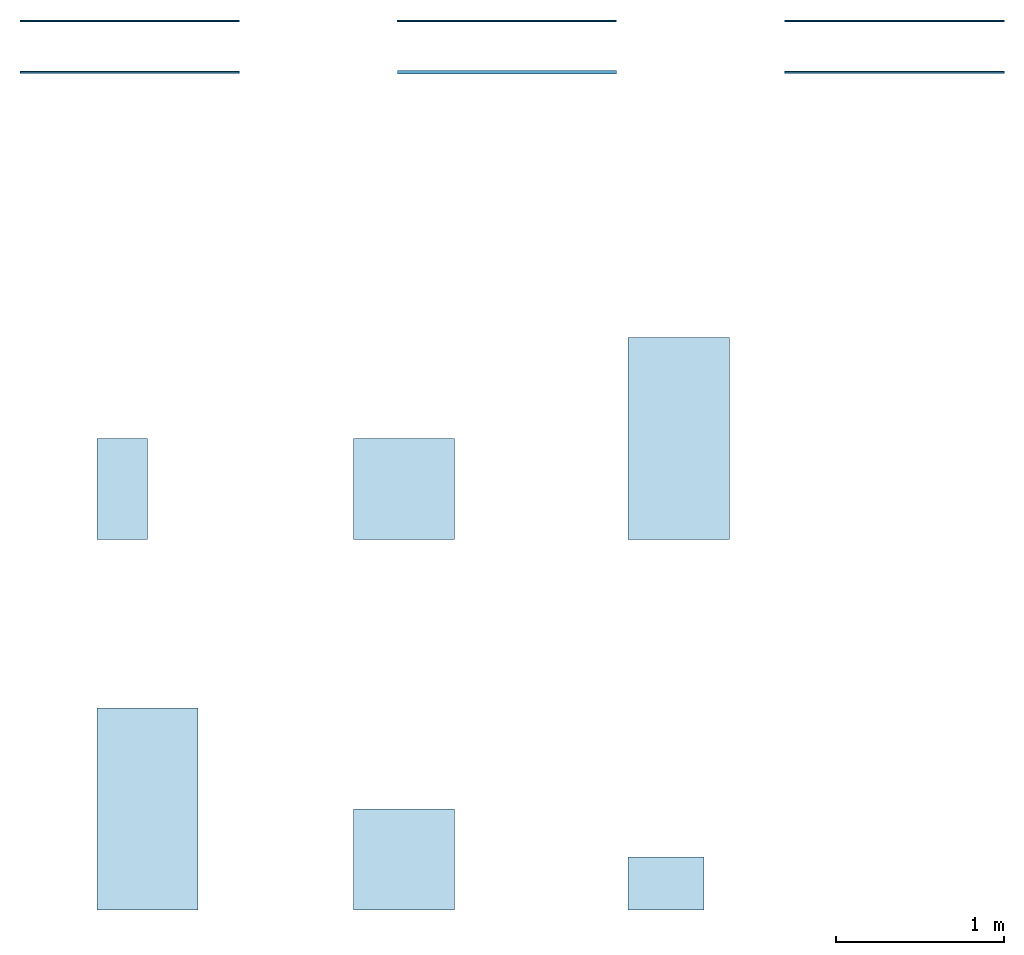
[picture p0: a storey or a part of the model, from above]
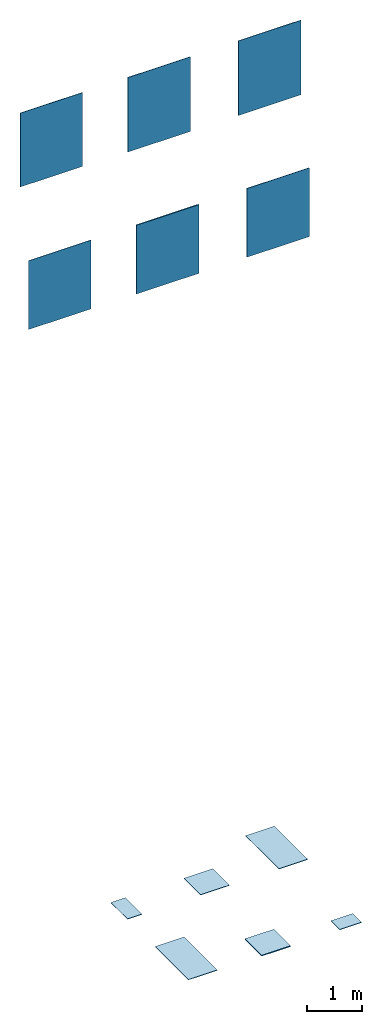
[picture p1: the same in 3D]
Properties of the parts of a building model (IFC2X3), part 2 of 2

# IfcWallStandardCase: Basic Wall:Wall_Tiles_Refin-Blended-Dark-60x60 OA84, Basic Wall:Wall_Tiles_Refin-Blended-Dark-60x60 OA84:333696
Type - Pset_CoveringCommon - Reference: N/A; Status: N/A; AcousticRating: N/A; FlammabilityRating: INERT; FragilityRating: INERT; Combustible: FALSE; SurfaceSpreadOfFlame: INERT; Finish: MATT; IsExternal: N/A; ThermalTransmittance: N/A; FireRating: INERT
Type - Pset_CoveringFlooring - HasNonSkidSurface: TRUE; HasAntiStaticSurface: FALSE
Type - Pset_Condition - AssessmentDate: N/A; AssessmentCondition: N/A; AssessmentDescription: N/A
Type - Pset_ServiceLife - ServiceLifeDuration: N/A; MeanTimeBetweenFailure: N/A
Type - COBie - AccessibilityPerformance: N/A; AssetIdentifier: N/A; AssetType: FIXED; BarCode: N/A; Category: Pr_35_93_96_19:Ceramic tiles; CodePerformance: BS 5385; Color: DARK; Constituents: N/A; Description: PORCELAIN STONEWARE TILE; DurationUnit: YEAR; ExpectedLife: N/A; Features: N/A; Grade: N/A; InstallationDate: 31/12/1900 23:59:59; Manufacturer: info@refin.it; Material: PORCELAIN STONEWARE; ModelNumber: OA84; ModelReference: OA84; Name: Blended_Dark_60X60 R; NominalHeight: 9 mm; NominalLength: 600 mm; NominalWidth: 600 mm; ReplacementCost: N/A; SerialNumber: N/A; Shape: SQUARE; Size: 60X60; SustainabilityPerformance: N/A; TagNumber: N/A; WarrantyDescription: N/A; WarrantyDurationLabor: N/A; WarrantyDurationParts: N/A; WarrantyDurationUnit: YEAR; WarrantyGuarantorLabor: N/A; WarrantyGuarantorParts: N/A; WarrantyStartDate: 31/12/1900 23:59:59
Type - DoPAndProductCertification - HarmonizedTechnicalSpecification: EN 14411:2015; DeclarationPerformanceNumber: CPR_01; UniqueIdentificationCodeOfTheProductType: Dry-pressed ceramic tiles,with water absorption Eb<0,5%; SystemOfAssessmentAndVerificationOfCostancyOfPperformance (AVCP): SYSTEM 4; NameAndIdentificationNumberOfNotifiedLaboratory: N/A; CertificateNumber: N/A; ReactionToFire: A1FL/A1; ReleaseOfDangerousSubstanceCadmium: NPD mg/dm2; ReleaseOfDangerousSubstanceLead: NPD mg/dm2; BreakingStrength: > 1300 N; BondStrengthAdhesion: NPD N/mm2; ThermalShockResistance: PASS; Tactility: NPD; DurabilityForInternalUse: PASS; DurabilityExternalUseFreezeThawResistance: PASS; VoluntaryOrNotSubjectToCEMarking: Y/N; IntendedUse: INTERNAL/EXTERNAL; TensileStrengthOrModulusOfRupture: > 35 N/mm2; SlipperinessDIN51130_RampWithOil: R10; SlipperinessDIN51097_RampBarefoot: N/A; SlipperinessDIN51131_Tribometer: N/A; SlipperinessBS7976-2_PendulumTester: ≥ 36 Wet; SlipperinessENV12633_PendulumTester: RD = N/A; SlipperinessXPCENTS16165_RampTest: N/A; SlipperinessBCRA_Tribometer: Asciutto > 0,40 / Bagnato > 0,40; SlipperinessBOT3000_Tribometer: > 0,42 Wet; UPECMarkCertification: N/A; UNIMarkCertification: N/A
Type - OtherThecnicalFeatures - DimensionsLengthAndWidth: 0.3; DimensionsThickness: 5; DimensionsStraightness: 0.3; DimensionsRectangularity: 0.3; DimensionsSurfaceFlatness: 0.4; SurfaceQuality: 5; WaterAbsorption: Ev<0.5%; ApparentDensity: N/A g/cm3; ModulusOfRupture: > 35 N/mm2; ImpactResistance: > 0.55; DeepAbrasionResistance: < 175 mm3; SurfaceAbrasionResistance: N/A (classe); LinearThermalExpansion: < 7 10-6/°C; MoistureExpansion: < 0.01; CrazingResistance: N/A; FrostResistance: RESISTENTE; ChemicalResistance: A,LA,HA (classe); StainsResistance: 5 (classe); ThermalConductivity: 1.3 W/m.K; ElectricalConductivity: N/A MW; CompressionResistance: 250 Mpa; HardnessMohsScale: N/A (classe); Light ReflectanceValueLRV: 16 %; LightAndColourFastness: N/A
Type - Ambiental Sustainability - EPDType: PRODUCT-SPECIFIC TYPE III EPD; EPDDocument: https://www.refin.it/download/certifications/REFIN_EPD_it.pdf; EnvironmentalProductDeclarationEPD: Y; ISO9001Certification: https://www.refin.it/download/certifications/iso9001.pdf; Ecolabel UE: Y/N; EcolabelCertification: https://www.refin.it/download/certifications/PEF_CeramicheRefin_IT.pdf; EMASCertification/Document: N/A; HealthProductDeclarationHPDCertification/self declaration: N/A; FicheDeDéclarationEnvironnementaleEtSanitaireFDESCertification: https://www.refin.it/download/certifications/refin_fdes.pdf; RecycledContentPreconsumerCertification: https://www.refin.it/download/certifications/leed.pdf; SolarReflectance_InitialValue: 25; SolarReflectance_After3YearValue: N/A; SolarReflectanceCertification: N/A; SolarReflectanceIndexSRICertification: N/A; ZeroVOCMineralBasedProduct: Y; VOCIndoorAirQualityCertification: N/A; RawMaterialSourceAndExtractionDocument: N/A; RecyclableProductPackaging: Y; REACHCompliant: Y; AsbestosFreeMaterial: Y; FormaldehydeFreeMaterial: Y; CAMCompliantDeclaration: N/A; ISO45001Certification: N/A; ISO50001Certification: N/A
Type - Pset_EnvironmentalImpactIndicator - Reference: N/A; FunctionalUnitReference: N/A; Unit: m2; LifeCyclePhase: A1,A2,A3,A4,A5,B1,B2,B3,B4,B5,B6,B7,C1,C2,C3,C4,D; ExpectedServiceLife: 60 YEARS; TotalPrimaryEnergyConsumptionPerUnit: 234; WaterConsumptionPerUnit: 0.0522; HazardousWastePerUnit: 0.00301; NonHazardousWastePerUnit: 10.4; ClimateChangePerUnit: 12.8; AtmosphericAcidificationPerUnit: 0.0485; RenewableEnergyConsumptionPerUnit: 44.5; NonRenewableEnergyConsumptionPerUnit: 189; ResourceDepletionPerUnit: 0.0000365; InertWastePerUnit: N/A; RadioactiveWastePerUnit: 0.00254; StratosphericOzoneLayerDestructionPerUnit: 0.0000000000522; PhotochemicalOzoneFormationPerUnit: 0.00302; EutrophicationPerUnit: 0.00445
Type - Pset_EnvironmentalImpactValues - TotalPrimaryEnergyConsumption: N/A; WaterConsumption: N/A; HazardousWaste: N/A; NonHazardousWaste: N/A; ClimateChange: N/A; AtmosphericAcidification: N/A; RenewableEnergyConsumption: N/A; NonRenewableEnergyConsumption: N/A; ResourceDepletion: N/A; InertWaste: N/A; RadioactiveWaste: N/A; StratosphericOzoneLayerDestruction: N/A; PhotochemicalOzoneFormation: N/A; Eutrophication: N/A; LeadInTime: N/A; Duration: N/A; LeadOutTime: N/A
Pset_ProductRequirements - Category: Walls
Pset_WallCommon - LoadBearing: no; ExtendToStructure: no
COBie - Category: Walls

# IfcWallStandardCase: Basic Wall:Wall_Tiles_Refin-Blended-Dark-GRIP-60x120 OB65, Basic Wall:Wall_Tiles_Refin-Blended-Dark-GRIP-60x120 OB65:335038
In: Level 0
Type - PredefinedType: STANDARD; Material: <Unnamed> 1 mm, Blended-Dark-GRIP-60x120 OB65 9 mm
Type - Pset_ConcreteElementGeneral - FireRating: INERT
Type - Pset_ElementShading - Roughness: 914.4 mm; Color: DARK
Type - Pset_FireRatingProperties - SurfaceSpreadOfFlame: INERT
Type - Pset_ManufacturerOccurrence - BarCode: N/A; SerialNumber: N/A
Type - Pset_ManufacturerTypeInformation - ArticleNumber: OB65; ModelReference: OB65; ModelLabel: DARK GRIP R 60X120; Manufacturer: info@refin.it; ProductionYear: N/A; GlobalTradeItemNumber: N/A; AssemblyPlace: N/A
Type - Pset_PrecastConcreteElementGeneral - SerialNumber: N/A
Type - Pset_ProductRequirements - Name: BlendedDark_GRIP_60X120 R; Category: Pr_35_93_96_19:Ceramic tiles
Type - Pset_QuantityTakeOff - Reference: N/A
Type - Pset_ReinforcementBarPitchOfWall - Description: PORCELAIN STONEWARE TILE; Reference: N/A
Type - Pset_WallCommon - Reference: N/A; IsExternal: no; AcousticRating: N/A; FireRating: INERT; SurfaceSpreadOfFlame: INERT
Type - Pset_Warranty - WarrantyContent: N/A; Exclusions: N/A; WarrantyEndDate: N/A; IsExtendedWarranty: N/A; WarrantyPeriod: N/A; PointOfContact: N/A
Type - Pset_CoveringCommon - Reference: N/A; Status: N/A; AcousticRating: N/A; FlammabilityRating: INERT; FragilityRating: INERT; Combustible: FALSE; SurfaceSpreadOfFlame: INERT; Finish: MATT; IsExternal: N/A; ThermalTransmittance: N/A; FireRating: INERT
Type - Pset_CoveringFlooring - HasNonSkidSurface: TRUE; HasAntiStaticSurface: FALSE
Type - Pset_Condition - AssessmentDate: N/A; AssessmentCondition: N/A; AssessmentDescription: N/A
Type - Pset_ServiceLife - ServiceLifeDuration: N/A; MeanTimeBetweenFailure: N/A
Type - COBie - AccessibilityPerformance: N/A; AssetIdentifier: N/A; AssetType: FIXED; BarCode: N/A; Category: Pr_35_93_96_19:Ceramic tiles; CodePerformance: BS 5385; Color: DARK; Constituents: N/A; Description: PORCELAIN STONEWARE TILE; DurationUnit: YEAR; ExpectedLife: N/A; Features: N/A; Grade: N/A; InstallationDate: 31/12/1900 23:59:59; Manufacturer: info@refin.it; Material: PORCELAIN STONEWARE; ModelNumber: OB65; ModelReference: OB65; Name: BlendedDark_GRIP_60X120 R; NominalHeight: 9 mm; NominalLength: 600 mm; NominalWidth: 1200 mm; ReplacementCost: N/A; SerialNumber: N/A; Shape: RECTANGULAR; Size: 60X120; SustainabilityPerformance: N/A; TagNumber: N/A; WarrantyDescription: N/A; WarrantyDurationLabor: N/A; WarrantyDurationParts: N/A; WarrantyDurationUnit: YEAR; WarrantyGuarantorLabor: N/A; WarrantyGuarantorParts: N/A; WarrantyStartDate: 31/12/1900 23:59:59
Type - DoPAndProductCertification - HarmonizedTechnicalSpecification: EN 14411:2015; DeclarationPerformanceNumber: CPR_01; UniqueIdentificationCodeOfTheProductType: Dry-pressed ceramic tiles,with water absorption Eb<0,5%; SystemOfAssessmentAndVerificationOfCostancyOfPperformance (AVCP): SYSTEM 4; NameAndIdentificationNumberOfNotifiedLaboratory: N/A; CertificateNumber: N/A; ReactionToFire: A1FL/A1; ReleaseOfDangerousSubstanceCadmium: NPD mg/dm2; ReleaseOfDangerousSubstanceLead: NPD mg/dm2; BreakingStrength: > 1300 N; BondStrengthAdhesion: NPD N/mm2; ThermalShockResistance: PASS; Tactility: NPD; DurabilityForInternalUse: PASS; DurabilityExternalUseFreezeThawResistance: PASS; VoluntaryOrNotSubjectToCEMarking: Y/N; IntendedUse: INTERNAL/EXTERNAL; TensileStrengthOrModulusOfRupture: > 35 N/mm2; SlipperinessDIN51130_RampWithOil: R11; SlipperinessDIN51097_RampBarefoot: N/A; SlipperinessDIN51131_Tribometer: N/A; SlipperinessBS7976-2_PendulumTester: N/A; SlipperinessENV12633_PendulumTester: RD = N/A; SlipperinessXPCENTS16165_RampTest: N/A; SlipperinessBCRA_Tribometer: Asciutto > 0,40 / Bagnato > 0,40; SlipperinessBOT3000_Tribometer: > 0,42 Wet; UPECMarkCertification: N/A; UNIMarkCertification: N/A
Type - OtherThecnicalFeatures - DimensionsLengthAndWidth: 0.3; DimensionsThickness: 5; DimensionsStraightness: 0.3; DimensionsRectangularity: 0.3; DimensionsSurfaceFlatness: 0.4; SurfaceQuality: 5; WaterAbsorption: Ev<0.5%; ApparentDensity: N/A g/cm3; ModulusOfRupture: > 35 N/mm2; ImpactResistance: > 0.55; DeepAbrasionResistance: < 175 mm3; SurfaceAbrasionResistance: N/A (classe); LinearThermalExpansion: < 7 10-6/°C; MoistureExpansion: < 0.01; CrazingResistance: N/A; FrostResistance: RESISTENTE; ChemicalResistance: A,LA,HA (classe); StainsResistance: 5 (classe); ThermalConductivity: 1.3 W/m.K; ElectricalConductivity: N/A MW; CompressionResistance: 250 Mpa; HardnessMohsScale: N/A (classe); Light ReflectanceValueLRV: 16 %; LightAndColourFastness: N/A
Type - Ambiental Sustainability - EPDType: PRODUCT-SPECIFIC TYPE III EPD; EPDDocument: https://www.refin.it/download/certifications/REFIN_EPD_it.pdf; EnvironmentalProductDeclarationEPD: Y; ISO9001Certification: https://www.refin.it/download/certifications/iso9001.pdf; Ecolabel UE: Y/N; EcolabelCertification: https://www.refin.it/download/certifications/PEF_CeramicheRefin_IT.pdf; EMASCertification/Document: N/A; HealthProductDeclarationHPDCertification/self declaration: N/A; FicheDeDéclarationEnvironnementaleEtSanitaireFDESCertification: https://www.refin.it/download/certifications/refin_fdes.pdf; RecycledContentPreconsumerCertification: https://www.refin.it/download/certifications/leed.pdf; SolarReflectance_InitialValue: 25; SolarReflectance_After3YearValue: N/A; SolarReflectanceCertification: N/A; SolarReflectanceIndexSRICertification: N/A; ZeroVOCMineralBasedProduct: Y; VOCIndoorAirQualityCertification: N/A; RawMaterialSourceAndExtractionDocument: N/A; RecyclableProductPackaging: Y; REACHCompliant: Y; AsbestosFreeMaterial: Y; FormaldehydeFreeMaterial: Y; CAMCompliantDeclaration: N/A; ISO45001Certification: N/A; ISO50001Certification: N/A
Type - Pset_EnvironmentalImpactIndicator - Reference: N/A; FunctionalUnitReference: N/A; Unit: m2; LifeCyclePhase: A1,A2,A3,A4,A5,B1,B2,B3,B4,B5,B6,B7,C1,C2,C3,C4,D; ExpectedServiceLife: 60 YEARS; TotalPrimaryEnergyConsumptionPerUnit: 234; WaterConsumptionPerUnit: 0.0522; HazardousWastePerUnit: 0.00301; NonHazardousWastePerUnit: 10.4; ClimateChangePerUnit: 12.8; AtmosphericAcidificationPerUnit: 0.0485; RenewableEnergyConsumptionPerUnit: 44.5; NonRenewableEnergyConsumptionPerUnit: 189; ResourceDepletionPerUnit: 0.0000365; InertWastePerUnit: N/A; RadioactiveWastePerUnit: 0.00254; StratosphericOzoneLayerDestructionPerUnit: 0.0000000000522; PhotochemicalOzoneFormationPerUnit: 0.00302; EutrophicationPerUnit: 0.00445
Type - Pset_EnvironmentalImpactValues - TotalPrimaryEnergyConsumption: N/A; WaterConsumption: N/A; HazardousWaste: N/A; NonHazardousWaste: N/A; ClimateChange: N/A; AtmosphericAcidification: N/A; RenewableEnergyConsumption: N/A; NonRenewableEnergyConsumption: N/A; ResourceDepletion: N/A; InertWaste: N/A; RadioactiveWaste: N/A; StratosphericOzoneLayerDestruction: N/A; PhotochemicalOzoneFormation: N/A; Eutrophication: N/A; LeadInTime: N/A; Duration: N/A; LeadOutTime: N/A
Pset_ProductRequirements - Category: Walls
Pset_WallCommon - LoadBearing: no; ExtendToStructure: no
COBie - Category: Walls

# IfcWallStandardCase: Basic Wall:Wall_Tiles_Refin-Blended-Dark-MURETTO_3D-31.5x45 NX92, Basic Wall:Wall_Tiles_Refin-Blended-Dark-MURETTO_3D-31.5x45 NX92:335882
In: Level 0
Type - PredefinedType: STANDARD; Material: <Unnamed> 1 mm, Blended-Dark-Muretto-3D-31.5x45 NX92 10 mm
Type - Pset_ConcreteElementGeneral - FireRating: INERT
Type - Pset_ElementShading - Roughness: 914.4 mm; Color: DARK
Type - Pset_FireRatingProperties - SurfaceSpreadOfFlame: INERT
Type - Pset_ManufacturerOccurrence - BarCode: N/A; SerialNumber: N/A
Type - Pset_ManufacturerTypeInformation - ArticleNumber: NX92; ModelReference: NX92; ModelLabel: DARK MURETTO 3D 31.5x45 R; Manufacturer: info@refin.it; ProductionYear: N/A; GlobalTradeItemNumber: N/A; AssemblyPlace: N/A
Type - Pset_PrecastConcreteElementGeneral - SerialNumber: N/A
Type - Pset_ProductRequirements - Name: Blended_Dark_MURETTO_3D_31.5X45 R; Category: Pr_35_93_96_19:Ceramic tiles
Type - Pset_QuantityTakeOff - Reference: N/A
Type - Pset_ReinforcementBarPitchOfWall - Description: PORCELAIN STONEWARE TILE; Reference: N/A
Type - Pset_WallCommon - Reference: N/A; IsExternal: no; AcousticRating: N/A; FireRating: INERT; SurfaceSpreadOfFlame: INERT
Type - Pset_Warranty - WarrantyContent: N/A; Exclusions: N/A; WarrantyEndDate: N/A; IsExtendedWarranty: N/A; WarrantyPeriod: N/A; PointOfContact: N/A
Type - Pset_CoveringCommon - Reference: N/A; Status: N/A; AcousticRating: N/A; FlammabilityRating: INERT; FragilityRating: INERT; Combustible: FALSE; SurfaceSpreadOfFlame: INERT; Finish: MATT; IsExternal: N/A; ThermalTransmittance: N/A; FireRating: INERT
Type - Pset_CoveringFlooring - HasNonSkidSurface: TRUE; HasAntiStaticSurface: FALSE
Type - Pset_Condition - AssessmentDate: N/A; AssessmentCondition: N/A; AssessmentDescription: N/A
Type - Pset_ServiceLife - ServiceLifeDuration: N/A; MeanTimeBetweenFailure: N/A
Type - COBie - AccessibilityPerformance: N/A; AssetIdentifier: N/A; AssetType: FIXED; BarCode: N/A; Category: Pr_35_93_96_19:Ceramic tiles; CodePerformance: BS 5385; Color: DARK; Constituents: N/A; Description: PORCELAIN STONEWARE TILE; DurationUnit: YEAR; ExpectedLife: N/A; Features: N/A; Grade: N/A; InstallationDate: 31/12/1900 23:59:59; Manufacturer: info@refin.it; Material: PORCELAIN STONEWARE; ModelNumber: NX92; ModelReference: NX92; Name: Blended_Dark_MURETTO_3D_31.5X45 R; NominalHeight: 10 mm; NominalLength: 315 mm; NominalWidth: 450 mm; ReplacementCost: N/A; SerialNumber: N/A; Shape: RECTANGULAR; Size: 31.5X45; SustainabilityPerformance: N/A; TagNumber: N/A; WarrantyDescription: N/A; WarrantyDurationLabor: N/A; WarrantyDurationParts: N/A; WarrantyDurationUnit: YEAR; WarrantyGuarantorLabor: N/A; WarrantyGuarantorParts: N/A; WarrantyStartDate: 31/12/1900 23:59:59
Type - DoPAndProductCertification - HarmonizedTechnicalSpecification: EN 14411:2015; DeclarationPerformanceNumber: CPR_01; UniqueIdentificationCodeOfTheProductType: Dry-pressed ceramic tiles,with water absorption Eb<0,5%; SystemOfAssessmentAndVerificationOfCostancyOfPperformance (AVCP): SYSTEM 4; NameAndIdentificationNumberOfNotifiedLaboratory: N/A; CertificateNumber: N/A; ReactionToFire: A1FL/A1; ReleaseOfDangerousSubstanceCadmium: NPD mg/dm2; ReleaseOfDangerousSubstanceLead: NPD mg/dm2; BreakingStrength: > 1300 N; BondStrengthAdhesion: NPD N/mm2; ThermalShockResistance: PASS; Tactility: NPD; DurabilityForInternalUse: PASS; DurabilityExternalUseFreezeThawResistance: PASS; VoluntaryOrNotSubjectToCEMarking: Y/N; IntendedUse: INTERNAL/EXTERNAL; TensileStrengthOrModulusOfRupture: > 35 N/mm2; SlipperinessDIN51130_RampWithOil: R10; SlipperinessDIN51097_RampBarefoot: N/A; SlipperinessDIN51131_Tribometer: N/A; SlipperinessBS7976-2_PendulumTester: ≥ 36 Wet; SlipperinessENV12633_PendulumTester: RD = N/A; SlipperinessXPCENTS16165_RampTest: N/A; SlipperinessBCRA_Tribometer: Asciutto > 0,40 / Bagnato > 0,40; SlipperinessBOT3000_Tribometer: > 0,42 Wet; UPECMarkCertification: N/A; UNIMarkCertification: N/A
Type - OtherThecnicalFeatures - DimensionsLengthAndWidth: 0.3; DimensionsThickness: 5; DimensionsStraightness: 0.3; DimensionsRectangularity: 0.3; DimensionsSurfaceFlatness: 0.4; SurfaceQuality: 5; WaterAbsorption: Ev<0.5%; ApparentDensity: N/A g/cm3; ModulusOfRupture: > 35 N/mm2; ImpactResistance: > 0.55; DeepAbrasionResistance: < 175 mm3; SurfaceAbrasionResistance: N/A (classe); LinearThermalExpansion: < 7 10-6/°C; MoistureExpansion: < 0.01; CrazingResistance: N/A; FrostResistance: RESISTENTE; ChemicalResistance: A,LA,HA (classe); StainsResistance: 5 (classe); ThermalConductivity: 1.3 W/m.K; ElectricalConductivity: N/A MW; CompressionResistance: 250 Mpa; HardnessMohsScale: N/A (classe); Light ReflectanceValueLRV: 16 %; LightAndColourFastness: N/A
Type - Ambiental Sustainability - EPDType: PRODUCT-SPECIFIC TYPE III EPD; EPDDocument: https://www.refin.it/download/certifications/REFIN_EPD_it.pdf; EnvironmentalProductDeclarationEPD: Y; ISO9001Certification: https://www.refin.it/download/certifications/iso9001.pdf; Ecolabel UE: Y/N; EcolabelCertification: https://www.refin.it/download/certifications/PEF_CeramicheRefin_IT.pdf; EMASCertification/Document: N/A; HealthProductDeclarationHPDCertification/self declaration: N/A; FicheDeDéclarationEnvironnementaleEtSanitaireFDESCertification: https://www.refin.it/download/certifications/refin_fdes.pdf; RecycledContentPreconsumerCertification: https://www.refin.it/download/certifications/leed.pdf; SolarReflectance_InitialValue: 25; SolarReflectance_After3YearValue: N/A; SolarReflectanceCertification: N/A; SolarReflectanceIndexSRICertification: N/A; ZeroVOCMineralBasedProduct: Y; VOCIndoorAirQualityCertification: N/A; RawMaterialSourceAndExtractionDocument: N/A; RecyclableProductPackaging: Y; REACHCompliant: Y; AsbestosFreeMaterial: Y; FormaldehydeFreeMaterial: Y; CAMCompliantDeclaration: N/A; ISO45001Certification: N/A; ISO50001Certification: N/A
Type - Pset_EnvironmentalImpactIndicator - Reference: N/A; FunctionalUnitReference: N/A; Unit: m2; LifeCyclePhase: A1,A2,A3,A4,A5,B1,B2,B3,B4,B5,B6,B7,C1,C2,C3,C4,D; ExpectedServiceLife: 60 YEARS; TotalPrimaryEnergyConsumptionPerUnit: 234; WaterConsumptionPerUnit: 0.0522; HazardousWastePerUnit: 0.00301; NonHazardousWastePerUnit: 10.4; ClimateChangePerUnit: 12.8; AtmosphericAcidificationPerUnit: 0.0485; RenewableEnergyConsumptionPerUnit: 44.5; NonRenewableEnergyConsumptionPerUnit: 189; ResourceDepletionPerUnit: 0.0000365; InertWastePerUnit: N/A; RadioactiveWastePerUnit: 0.00254; StratosphericOzoneLayerDestructionPerUnit: 0.0000000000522; PhotochemicalOzoneFormationPerUnit: 0.00302; EutrophicationPerUnit: 0.00445
Type - Pset_EnvironmentalImpactValues - TotalPrimaryEnergyConsumption: N/A; WaterConsumption: N/A; HazardousWaste: N/A; NonHazardousWaste: N/A; ClimateChange: N/A; AtmosphericAcidification: N/A; RenewableEnergyConsumption: N/A; NonRenewableEnergyConsumption: N/A; ResourceDepletion: N/A; InertWaste: N/A; RadioactiveWaste: N/A; StratosphericOzoneLayerDestruction: N/A; PhotochemicalOzoneFormation: N/A; Eutrophication: N/A; LeadInTime: N/A; Duration: N/A; LeadOutTime: N/A
Pset_ProductRequirements - Category: Walls
Pset_WallCommon - LoadBearing: no; ExtendToStructure: no
COBie - Category: Walls

# IfcWallStandardCase: Basic Wall:Wall_Tiles_Refin-Blended-Dark-OUT2.0-60x60 OA94, Basic Wall:Wall_Tiles_Refin-Blended-Dark-OUT2.0-60x60 OA94:335490
In: Level 0
Type - PredefinedType: STANDARD; Material: <Unnamed> 1 mm, Blended-Dark-OUT2.0-60x60 OA94 20 mm
Type - Pset_ConcreteElementGeneral - FireRating: INERT
Type - Pset_ElementShading - Roughness: 914.4 mm; Color: DARK
Type - Pset_FireRatingProperties - SurfaceSpreadOfFlame: INERT
Type - Pset_ManufacturerOccurrence - BarCode: N/A; SerialNumber: N/A
Type - Pset_ManufacturerTypeInformation - ArticleNumber: OA94; ModelReference: OA94; ModelLabel: DARK OUT2.0 60X60 R; Manufacturer: info@refin.it; ProductionYear: N/A; GlobalTradeItemNumber: N/A; AssemblyPlace: N/A
Type - Pset_PrecastConcreteElementGeneral - SerialNumber: N/A
Type - Pset_ProductRequirements - Name: Blended_Dark_OUT2.0 60X60 R; Category: Pr_35_93_96_19:Ceramic tiles
Type - Pset_QuantityTakeOff - Reference: N/A
Type - Pset_ReinforcementBarPitchOfWall - Description: PORCELAIN STONEWARE TILE; Reference: N/A
Type - Pset_WallCommon - Reference: N/A; IsExternal: no; AcousticRating: N/A; FireRating: INERT; SurfaceSpreadOfFlame: INERT
Type - Pset_Warranty - WarrantyContent: N/A; Exclusions: N/A; WarrantyEndDate: N/A; IsExtendedWarranty: N/A; WarrantyPeriod: N/A; PointOfContact: N/A
Type - Pset_CoveringCommon - Reference: N/A; Status: N/A; AcousticRating: N/A; FlammabilityRating: INERT; FragilityRating: INERT; Combustible: FALSE; SurfaceSpreadOfFlame: INERT; Finish: MATT; IsExternal: N/A; ThermalTransmittance: N/A; FireRating: INERT
Type - Pset_CoveringFlooring - HasNonSkidSurface: TRUE; HasAntiStaticSurface: FALSE
Type - Pset_Condition - AssessmentDate: N/A; AssessmentCondition: N/A; AssessmentDescription: N/A
Type - Pset_ServiceLife - ServiceLifeDuration: N/A; MeanTimeBetweenFailure: N/A
Type - COBie - AccessibilityPerformance: N/A; AssetIdentifier: N/A; AssetType: FIXED; BarCode: N/A; Category: Pr_35_93_96_19:Ceramic tiles; CodePerformance: BS 5385; Color: DARK; Constituents: N/A; Description: PORCELAIN STONEWARE TILE; DurationUnit: YEAR; ExpectedLife: N/A; Features: N/A; Grade: N/A; InstallationDate: 31/12/1900 23:59:59; Manufacturer: info@refin.it; Material: PORCELAIN STONEWARE; ModelNumber: OA94; ModelReference: OA94; Name: Blended_Dark_OUT2.0 60X60 R; NominalHeight: 20 mm; NominalLength: 600 mm; NominalWidth: 600 mm; ReplacementCost: N/A; SerialNumber: N/A; Shape: SQUARE; Size: 60X60; SustainabilityPerformance: N/A; TagNumber: N/A; WarrantyDescription: N/A; WarrantyDurationLabor: N/A; WarrantyDurationParts: N/A; WarrantyDurationUnit: YEAR; WarrantyGuarantorLabor: N/A; WarrantyGuarantorParts: N/A; WarrantyStartDate: 31/12/1900 23:59:59
Type - DoPAndProductCertification - HarmonizedTechnicalSpecification: EN 14411:2015; DeclarationPerformanceNumber: CPR_01; UniqueIdentificationCodeOfTheProductType: Dry-pressed ceramic tiles,with water absorption Eb<0,5%; SystemOfAssessmentAndVerificationOfCostancyOfPperformance (AVCP): SYSTEM 4; NameAndIdentificationNumberOfNotifiedLaboratory: N/A; CertificateNumber: N/A; ReactionToFire: A1FL/A1; ReleaseOfDangerousSubstanceCadmium: NPD mg/dm2; ReleaseOfDangerousSubstanceLead: NPD mg/dm2; BreakingStrength: > 1300 N; BondStrengthAdhesion: NPD N/mm2; ThermalShockResistance: PASS; Tactility: NPD; DurabilityForInternalUse: PASS; DurabilityExternalUseFreezeThawResistance: PASS; VoluntaryOrNotSubjectToCEMarking: Y/N; IntendedUse: INTERNAL/EXTERNAL; TensileStrengthOrModulusOfRupture: > 35 N/mm2; SlipperinessDIN51130_RampWithOil: R11; SlipperinessDIN51097_RampBarefoot: A+B+C; SlipperinessDIN51131_Tribometer: N/A; SlipperinessBS7976-2_PendulumTester: N/A; SlipperinessENV12633_PendulumTester: RD = N/A; SlipperinessXPCENTS16165_RampTest: N/A; SlipperinessBCRA_Tribometer: Asciutto > 0,40 / Bagnato > 0,40; SlipperinessBOT3000_Tribometer: > 0,42 Wet; UPECMarkCertification: N/A; UNIMarkCertification: N/A
Type - OtherThecnicalFeatures - DimensionsLengthAndWidth: 0.3; DimensionsThickness: 5; DimensionsStraightness: 0.3; DimensionsRectangularity: 0.3; DimensionsSurfaceFlatness: 0.4; SurfaceQuality: 5; WaterAbsorption: Ev<0.5%; ApparentDensity: N/A g/cm3; ModulusOfRupture: > 35 N/mm2; ImpactResistance: > 0.55; DeepAbrasionResistance: < 175 mm3; SurfaceAbrasionResistance: N/A (classe); LinearThermalExpansion: < 7 10-6/°C; MoistureExpansion: < 0.01; CrazingResistance: N/A; FrostResistance: RESISTENTE; ChemicalResistance: A,LA,HA (classe); StainsResistance: 5 (classe); ThermalConductivity: 1.3 W/m.K; ElectricalConductivity: N/A MW; CompressionResistance: 250 Mpa; HardnessMohsScale: N/A (classe); Light ReflectanceValueLRV: 16 %; LightAndColourFastness: N/A
Type - Ambiental Sustainability - EPDType: PRODUCT-SPECIFIC TYPE III EPD; EPDDocument: https://www.refin.it/download/certifications/REFIN_EPD_it.pdf; EnvironmentalProductDeclarationEPD: Y; ISO9001Certification: https://www.refin.it/download/certifications/iso9001.pdf; Ecolabel UE: Y/N; EcolabelCertification: https://www.refin.it/download/certifications/PEF_CeramicheRefin_IT.pdf; EMASCertification/Document: N/A; HealthProductDeclarationHPDCertification/self declaration: N/A; FicheDeDéclarationEnvironnementaleEtSanitaireFDESCertification: https://www.refin.it/download/certifications/refin_fdes.pdf; RecycledContentPreconsumerCertification: https://www.refin.it/download/certifications/leed.pdf; SolarReflectance_InitialValue: 25; SolarReflectance_After3YearValue: N/A; SolarReflectanceCertification: N/A; SolarReflectanceIndexSRICertification: N/A; ZeroVOCMineralBasedProduct: Y; VOCIndoorAirQualityCertification: N/A; RawMaterialSourceAndExtractionDocument: N/A; RecyclableProductPackaging: Y; REACHCompliant: Y; AsbestosFreeMaterial: Y; FormaldehydeFreeMaterial: Y; CAMCompliantDeclaration: N/A; ISO45001Certification: N/A; ISO50001Certification: N/A
Type - Pset_EnvironmentalImpactIndicator - Reference: N/A; FunctionalUnitReference: N/A; Unit: m2; LifeCyclePhase: A1,A2,A3,A4,A5,B1,B2,B3,B4,B5,B6,B7,C1,C2,C3,C4,D; ExpectedServiceLife: 60 YEARS; TotalPrimaryEnergyConsumptionPerUnit: 234; WaterConsumptionPerUnit: 0.0522; HazardousWastePerUnit: 0.00301; NonHazardousWastePerUnit: 10.4; ClimateChangePerUnit: 12.8; AtmosphericAcidificationPerUnit: 0.0485; RenewableEnergyConsumptionPerUnit: 44.5; NonRenewableEnergyConsumptionPerUnit: 189; ResourceDepletionPerUnit: 0.0000365; InertWastePerUnit: N/A; RadioactiveWastePerUnit: 0.00254; StratosphericOzoneLayerDestructionPerUnit: 0.0000000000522; PhotochemicalOzoneFormationPerUnit: 0.00302; EutrophicationPerUnit: 0.00445
Type - Pset_EnvironmentalImpactValues - TotalPrimaryEnergyConsumption: N/A; WaterConsumption: N/A; HazardousWaste: N/A; NonHazardousWaste: N/A; ClimateChange: N/A; AtmosphericAcidification: N/A; RenewableEnergyConsumption: N/A; NonRenewableEnergyConsumption: N/A; ResourceDepletion: N/A; InertWaste: N/A; RadioactiveWaste: N/A; StratosphericOzoneLayerDestruction: N/A; PhotochemicalOzoneFormation: N/A; Eutrophication: N/A; LeadInTime: N/A; Duration: N/A; LeadOutTime: N/A
Pset_ProductRequirements - Category: Walls
Pset_WallCommon - LoadBearing: no; ExtendToStructure: no
COBie - Category: Walls
